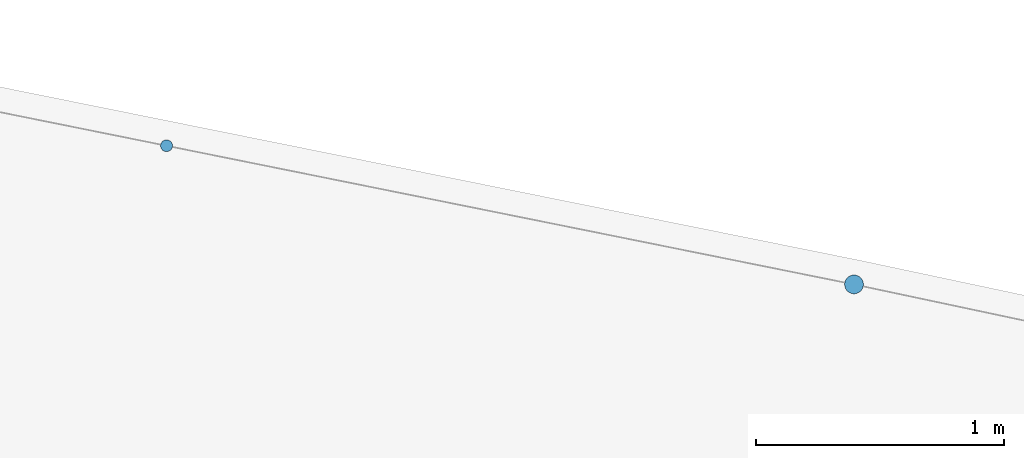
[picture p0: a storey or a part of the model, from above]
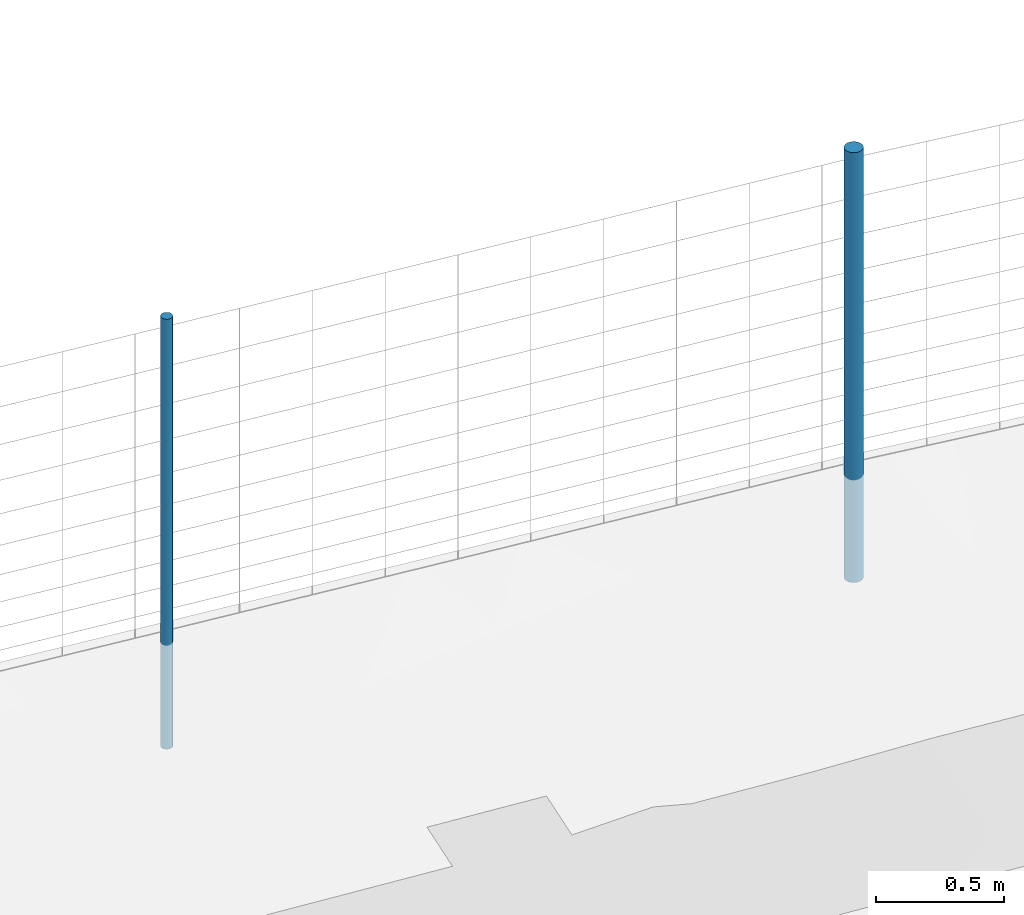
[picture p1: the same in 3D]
Properties of the parts of a building model (IFC4)

# File
Description: ViewDefinition [CoordinationView]
File name: Casa_Sobreposta_Implantada.ifc
Time: 2026-10-02T16:17:10
Written by: IfcOpenShell 0.8.0
Made in: IfcOpenShell 0.8.0

# IfcProject, Casa / Lares · R09 · Telhado tradicional
Pset_CasaModel - Design: R09 / telha / lower hybrid podium and ground-supported parking; ReferenceFile: 260617_CasaDFL_Estrutura_Terreno.ifc; ModelStatus: DESIGN_STUDY; North: Survey grid +Y; Ramp: No exterior pedestrian ramp or vehicular bridge; EngineeringStatus: Member sizes, foundations, connections, bracing and environmental performance not verified; GroundFFL_m: 14.65; AreaLimit_m2: 250; CountedGeometricArea_m2: 163.712; GreenhouseExcludedByUser: no; BalconiesExcludedByClient: yes; CoveredGroundBalcony_m2: 132.714; PlanningComplianceEstablished: no; AreaBasis: Client-confirmed 250 m2 allowance: parking, cistern, balconies and open greenhouse excluded; enclosed upper rooms and stair enclosures count. Any storage would count. Geometric study, no independent PDM verification.

# IfcSite, Lares · Rua das Mercês · artigo 4771
Pset_SurveySource - File: GN_09.26_213 Lares.dwg; SHA256: 0bca0a0751148bad1398f92d81b795428f94a57fea5e37dec0e125cea70402a1; Area_m2: 1636.5; BoundaryHandle: 31B; CoordinateReference: PT-TM06 / ETRS89; TerrainStatus: Proposed grading; original survey in separate IFC

# IfcBuilding, Casa Sobreposta
Pset_CasaPlacement - GroundFloorSurveyLevel_m: 14.65; UpperFloor: no; MoveEast_m: 3; MoveSouth_m: 0.5; RotationFromGridEast_deg: -8.5; BoundarySetbackRequired_m: 3; RuleBasis: User project constraint
Pset_CasaRevision09 - Variant: telha; HybridPodium: yes; ParkingGroundSupported: yes; GroundFFL_m: 14.65; TerraceFFL_m: 14.61; VehicularBridgeLength_m: 0; AccessGabions: no; Cut_m3: 96.4024; Fill_m3: 5.19635; EarthworkExclusions: Topsoil, foundation/service trenches, soil replacement, construction working space and bulking; CoveredGroundBalconyClassification: EXCLUDED_BY_CLIENT; WindCapacityVerified: no

# IfcBuildingStorey (2)
In: Casa Sobreposta
Name | Elevation (m)
00 · Habitação e estacionamento | 14.65
-01 · Cisterna sob o terraço | 12.05

# IfcSpace (11)
In: 00 · Habitação e estacionamento
Pset_CasaProvenance - DesignSource: Casa Sobreposta / configuration.json; ReferenceFile: 260617_CasaDFL_Estrutura_Terreno.ifc; ConstructionBasis: DESIGN_ASSUMPTION; Note: Functional zone from configurator; overlaps with partition footprints removed on ground floor. Not certified usable floor area.
Name | PredefinedType | NetFloorArea (m2)
Sala | INTERNAL | 31.359
Cozinha | INTERNAL | 9.94248
Banho | INTERNAL | 7.19804
WC | INTERNAL | 1.231
Serviço | INTERNAL | 4.16058
Acesso IS | INTERNAL | 3.99017
Quarto 1 | INTERNAL | 13.1145
Quarto 2 | INTERNAL | 13.1145
Quarto / escritório | INTERNAL | 37.8909
Circulação | INTERNAL | 18.1139
Estacionamento · 2 lugares | EXTERNAL | 32.55

# IfcAnnotation (4)
Pset_CasaProvenance - DesignSource: Casa Sobreposta / configuration.json; ReferenceFile: 260617_CasaDFL_Estrutura_Terreno.ifc; ConstructionBasis: DESIGN_ASSUMPTION
Name | In
Lugar P1 · 2.50 x 5.00 m | 00 · Habitação e estacionamento
Lugar P2 · 2.50 x 5.00 m | 00 · Habitação e estacionamento
Limite levantado · 31B | Lares · Rua das Mercês · artigo 4771
Afastamento de implantação · 3 m | Lares · Rua das Mercês · artigo 4771

# IfcBeam (11)
In: 00 · Habitação e estacionamento
Material: Betão armado / Stahlbeton
Pset_CasaProvenance - DesignSource: Casa Sobreposta / configuration.json; ReferenceFile: 260617_CasaDFL_Estrutura_Terreno.ifc; ConstructionBasis: DESIGN_ASSUMPTION
Name
8 x Pódio suspenso · viga transversal
3 x Pódio suspenso · viga longitudinal

# IfcBeam: TIMBER0.140x0.220 / timber (5)
In: 00 · Habitação e estacionamento
Type - Material: Madeira / Bauholz
Pset_CasaProvenance - DesignSource: Casa Sobreposta / configuration.json; ReferenceFile: 260617_CasaDFL_Estrutura_Terreno.ifc; ConstructionBasis: DESIGN_ASSUMPTION; Note: Visible timber concept; strength class, deflection, stability, wind and fire design pending.

# IfcBeam: TIMBER0.160x0.220 / timber (4)
In: 00 · Habitação e estacionamento
Type - Material: Madeira / Bauholz
Pset_CasaProvenance - DesignSource: Casa Sobreposta / configuration.json; ReferenceFile: 260617_CasaDFL_Estrutura_Terreno.ifc; ConstructionBasis: DESIGN_ASSUMPTION; Note: Visible timber concept; strength class, deflection, stability, wind and fire design pending.
Name
2 x Cobertura · frechal longitudinal
2 x Varanda coberta · frechal

# IfcBeam: TIMBER0.160x0.240 / timber (12)
In: 00 · Habitação e estacionamento
Type - Material: Madeira / Bauholz
Pset_CasaProvenance - DesignSource: Casa Sobreposta / configuration.json; ReferenceFile: 260617_CasaDFL_Estrutura_Terreno.ifc; ConstructionBasis: DESIGN_ASSUMPTION; Note: Visible timber concept; strength class, deflection, stability, wind and fire design pending.

# IfcBuildingElementProxy: Acesso · caixa de retenção de sedimentos (2)
In: Lares · Rua das Mercês · artigo 4771
PredefinedType: USERDEFINED; Material: Caleiras · betão
Pset_CasaProvenance - DesignSource: Casa Sobreposta / configuration.json; ReferenceFile: 260617_CasaDFL_Estrutura_Terreno.ifc; ConstructionBasis: DESIGN_ASSUMPTION

# IfcBuildingElementProxy: Acesso · dreno lateral raso · leito drenante (74)
In: Lares · Rua das Mercês · artigo 4771
PredefinedType: USERDEFINED; Material: Brita drenante
Pset_CasaProvenance - DesignSource: Casa Sobreposta / configuration.json; ReferenceFile: 260617_CasaDFL_Estrutura_Terreno.ifc; ConstructionBasis: DESIGN_ASSUMPTION; Note: R09 concept geometry; dimensions and connections not structurally verified.

# IfcBuildingElementProxy: Cisterna · água a 2,00 m, hipótese
In: -01 · Cisterna sob o terraço
PredefinedType: USERDEFINED; Material: Água pluvial · nível ilustrativo
Pset_CasaProvenance - DesignSource: Casa Sobreposta / configuration.json; ReferenceFile: 260617_CasaDFL_Estrutura_Terreno.ifc; ConstructionBasis: DESIGN_ASSUMPTION; Note: Illustrative water envelope, not concrete or a certified operating capacity.

# IfcBuildingElementProxy: Cobertura · caleira pluvial para cisterna (2)
In: 00 · Habitação e estacionamento
PredefinedType: USERDEFINED; Material: Aço galvanizado / Stahl verzinkt
Pset_CasaProvenance - DesignSource: Casa Sobreposta / configuration.json; ReferenceFile: 260617_CasaDFL_Estrutura_Terreno.ifc; ConstructionBasis: DESIGN_ASSUMPTION

# IfcBuildingElementProxy: Interceção · caleira estacionamento · leito drenante (8)
In: Lares · Rua das Mercês · artigo 4771
PredefinedType: USERDEFINED; Material: Brita drenante
Pset_CasaProvenance - DesignSource: Casa Sobreposta / configuration.json; ReferenceFile: 260617_CasaDFL_Estrutura_Terreno.ifc; ConstructionBasis: DESIGN_ASSUMPTION; Note: R09 concept geometry; dimensions and connections not structurally verified.

# IfcBuildingElementProxy: Interceção · caleira rua · leito drenante (8)
In: Lares · Rua das Mercês · artigo 4771
PredefinedType: USERDEFINED; Material: Brita drenante
Pset_CasaProvenance - DesignSource: Casa Sobreposta / configuration.json; ReferenceFile: 260617_CasaDFL_Estrutura_Terreno.ifc; ConstructionBasis: DESIGN_ASSUMPTION; Note: R09 concept geometry; dimensions and connections not structurally verified.

# IfcBuildingElementProxy: Trepadeiras · floreira (10)
In: 00 · Habitação e estacionamento
PredefinedType: USERDEFINED; Material: Betão armado / Stahlbeton
Pset_CasaProvenance - DesignSource: Casa Sobreposta / configuration.json; ReferenceFile: 260617_CasaDFL_Estrutura_Terreno.ifc; ConstructionBasis: DESIGN_ASSUMPTION; Note: Indicative planter; soil volume, irrigation, root space and waterproofing to design.

# IfcColumn (48)
In: 00 · Habitação e estacionamento
Material: Betão armado / Stahlbeton
Pset_CasaProvenance - DesignSource: Casa Sobreposta / configuration.json; ReferenceFile: 260617_CasaDFL_Estrutura_Terreno.ifc
Name | ConstructionBasis
18 x Casa térrea · pedestal | ADAPTED_REFERENCE
24 x Pódio suspenso · apoio sobre o terreno | DESIGN_ASSUMPTION
6 x Varanda coberta · pedestal enterrado | DESIGN_ASSUMPTION

# IfcColumn: IPE240 / steel (18)
In: 00 · Habitação e estacionamento
Type - Material: Aço pintado / Stahl lackiert
Pset_CasaProvenance - DesignSource: Casa Sobreposta / configuration.json; ReferenceFile: 260617_CasaDFL_Estrutura_Terreno.ifc; ConstructionBasis: ADAPTED_REFERENCE; Note: Reference section; spans, stability and connections require design.

# IfcColumn: RHS80x60x4 / steel (4)
In: 00 · Habitação e estacionamento
Type - Material: Aço pintado / Stahl lackiert
Pset_CasaProvenance - DesignSource: Casa Sobreposta / configuration.json; ReferenceFile: 260617_CasaDFL_Estrutura_Terreno.ifc; ConstructionBasis: DESIGN_ASSUMPTION; Note: Reference section; spans, stability and connections require design.

# IfcColumn: TIMBER0.160x0.160 / timber (24)
In: 00 · Habitação e estacionamento
Type - Material: Madeira / Bauholz
Pset_CasaProvenance - DesignSource: Casa Sobreposta / configuration.json; ReferenceFile: 260617_CasaDFL_Estrutura_Terreno.ifc; ConstructionBasis: DESIGN_ASSUMPTION; Note: Visible timber concept; strength class, deflection, stability, wind and fire design pending.

# IfcCovering (15)
Pset_CasaProvenance - DesignSource: Casa Sobreposta / configuration.json; ReferenceFile: 260617_CasaDFL_Estrutura_Terreno.ifc; ConstructionBasis: DESIGN_ASSUMPTION
Name | In | PredefinedType | Material
2 x Cobertura · forro de madeira | 00 · Habitação e estacionamento | CLADDING | Madeira / Bauholz
2 x Cobertura · isolamento | 00 · Habitação e estacionamento | INSULATION | Lã mineral / Mineralwolle 2
2 x Cobertura · membrana | 00 · Habitação e estacionamento | MEMBRANE | Membrana impermeável — hipótese
Cobertura · telhas individualizadas 1 | 00 · Habitação e estacionamento | ROOFING | Telha cerâmica · tile0 | Pset_CasaProvenance - Note: R09 concept geometry; dimensions and connections not structurally verified.
Cobertura · telhas individualizadas 2 | 00 · Habitação e estacionamento | ROOFING | Telha cerâmica · tile1 | Pset_CasaProvenance - Note: R09 concept geometry; dimensions and connections not structurally verified.
Cobertura · telhas individualizadas 3 | 00 · Habitação e estacionamento | ROOFING | Telha cerâmica · tile2 | Pset_CasaProvenance - Note: R09 concept geometry; dimensions and connections not structurally verified.
Cobertura · cumeeira cerâmica | 00 · Habitação e estacionamento | ROOFING | Telha cerâmica · tile1
Cisterna · camada drenante 100 mm | -01 · Cisterna sob o terraço | FLOORING | Brita drenante
Cisterna · impermeabilização poente | -01 · Cisterna sob o terraço | MEMBRANE | Membrana impermeável — hipótese
Cisterna · impermeabilização norte | -01 · Cisterna sob o terraço | MEMBRANE | Membrana impermeável — hipótese
Cisterna · impermeabilização sul | -01 · Cisterna sob o terraço | MEMBRANE | Membrana impermeável — hipótese
Cisterna · impermeabilização nascente | -01 · Cisterna sob o terraço | MEMBRANE | Membrana impermeável — hipótese

# IfcDoor (18)
In: 00 · Habitação e estacionamento
PredefinedType: DOOR
Pset_CasaProvenance - DesignSource: Casa Sobreposta / configuration.json; ReferenceFile: 260617_CasaDFL_Estrutura_Terreno.ifc
Name | OverallHeight (m) | OverallWidth (m) | OperationType | Material | ConstructionBasis
Porta interior 1 | 2.1 | 0.830093 | SINGLE_SWING_LEFT | OSB | ADAPTED_REFERENCE
Porta interior 2 | 2.1 | 0.830093 | SINGLE_SWING_LEFT | OSB | ADAPTED_REFERENCE
Porta interior 3 | 2.1 | 0.730086 | SINGLE_SWING_LEFT | OSB | ADAPTED_REFERENCE
Porta interior 4 | 2.1 | 0.830092 | SINGLE_SWING_LEFT | OSB | ADAPTED_REFERENCE
Porta interior 5 | 2.1 | 0.830077 | SINGLE_SWING_LEFT | OSB | ADAPTED_REFERENCE
Porta interior 6 | 2.1 | 0.730017 | SINGLE_SWING_LEFT | OSB | ADAPTED_REFERENCE
Porta do estacionamento | 2.1 | 0.83 | SINGLE_SWING_LEFT | Aço pintado / Stahl lackiert | ADAPTED_REFERENCE
Folha de correr sul 2 | 3 | 1.97133 | SLIDING_TO_LEFT | Vidro / Normalglas | DESIGN_ASSUMPTION
Folha de correr sul 4 | 3 | 1.97133 | SLIDING_TO_LEFT | Vidro / Normalglas | DESIGN_ASSUMPTION
Folha de correr sul 6 | 3 | 1.97133 | SLIDING_TO_LEFT | Vidro / Normalglas | DESIGN_ASSUMPTION
Folha de correr sul 8 | 3 | 1.97133 | SLIDING_TO_LEFT | Vidro / Normalglas | DESIGN_ASSUMPTION
Folha de correr sul 10 | 3 | 1.97133 | SLIDING_TO_LEFT | Vidro / Normalglas | DESIGN_ASSUMPTION
Folha de correr sul 12 | 3 | 0.614 | SLIDING_TO_LEFT | Vidro / Normalglas | DESIGN_ASSUMPTION
Fachada poente integralmente envidraçada · módulo 4 | 3 | 1.55 | SLIDING_TO_LEFT | Vidro / Normalglas | DESIGN_ASSUMPTION | Pset_CasaGlazedFacade - Revision: R02 · kiwi pergola; Facade: WEST / highlighted end in user sketch; Infill: Full-height glazing; no opaque infill; GlazingSpecification: 8 mm nominal representation only; insulated safety glazing assembly to specify
2 x Contentor · porta dupla | 2.39 | 1.17 | SINGLE_SWING_LEFT | Contentor · pintura 1 | DESIGN_ASSUMPTION
2 x Contentor · porta dupla | 2.39 | 1.17 | SINGLE_SWING_LEFT | Contentor · pintura 2 | DESIGN_ASSUMPTION

# IfcElementAssembly: CISTERN_PODIUM, Pódio · terraço, casa térrea e cisterna
In: 00 · Habitação e estacionamento
PredefinedType: USERDEFINED
Pset_CasaProvenance - DesignSource: Casa Sobreposta / configuration.json; ReferenceFile: 260617_CasaDFL_Estrutura_Terreno.ifc; ConstructionBasis: DESIGN_ASSUMPTION
Pset_CasaUndercroft - NaturalGroundRetained: no; EnclosedStorage: no; Use: Open ventilated sloping void; not a habitable or storage storey; StructuralStatus: Concept slab, beams, piers and foundation sizes; geotechnical and structural design pending
Pset_CasaPodium - TankGrossPlan_m2: 23; TankBaseLevel_m: 12.05; MinimumInternalHeight_m: 2.31; FloorSupport: Hybrid podium: west spans retained slope; local formation east; parking supported by soil; PlanningAssumption: Cistern excluded from 250 m2 by explicit user confirmation 2026-10-02

# IfcElementAssembly: COVERED_PODIUM_BALCONY, Varanda coberta · continuação integral da cobertura
In: 00 · Habitação e estacionamento
PredefinedType: USERDEFINED
Pset_CasaProvenance - DesignSource: Casa Sobreposta / configuration.json; ReferenceFile: 260617_CasaDFL_Estrutura_Terreno.ifc; ConstructionBasis: DESIGN_ASSUMPTION

# IfcElementAssembly: EXISTING_SHIPPING_CONTAINER (2)
In: 00 · Habitação e estacionamento
PredefinedType: USERDEFINED
Pset_CasaProvenance - DesignSource: Casa Sobreposta / configuration.json; ReferenceFile: 260617_CasaDFL_Estrutura_Terreno.ifc; ConstructionBasis: DESIGN_ASSUMPTION
Pset_CasaExistingContext - Length_m: 6; WidthAssumed_m: 2.44; HeightAssumed_m: 2.59; Location: Digitised visible roofs from signed orthophoto; fitted 6 x 2.44 m, provisional +/- 0.50 m, verify ground corners; Status: Existing context; not included in new building setback or new floor-area schedule; Colour: Illustrative, condition not surveyed
Name
Contentor existente 1 · 6 m
Contentor existente 2 · 6 m

# IfcElementAssembly: LIVING_SHADE_TRELLIS, Fachada sul e pátio · estrutura e trepadeiras
In: 00 · Habitação e estacionamento
PredefinedType: USERDEFINED
Pset_CasaProvenance - DesignSource: Casa Sobreposta / configuration.json; ReferenceFile: 260617_CasaDFL_Estrutura_Terreno.ifc; ConstructionBasis: DESIGN_ASSUMPTION

# IfcFooting (64)
Material: Betão armado / Stahlbeton
Pset_CasaProvenance - DesignSource: Casa Sobreposta / configuration.json; ReferenceFile: 260617_CasaDFL_Estrutura_Terreno.ifc
Name | In | PredefinedType | ConstructionBasis
18 x Casa térrea · sapata | 00 · Habitação e estacionamento | PAD_FOOTING | ADAPTED_REFERENCE
Cisterna · sapata corrida poente | -01 · Cisterna sob o terraço | STRIP_FOOTING | DESIGN_ASSUMPTION
Cisterna · sapata corrida norte | -01 · Cisterna sob o terraço | STRIP_FOOTING | DESIGN_ASSUMPTION
Cisterna · sapata corrida sul | -01 · Cisterna sob o terraço | STRIP_FOOTING | DESIGN_ASSUMPTION
Cisterna · sapata corrida nascente | -01 · Cisterna sob o terraço | STRIP_FOOTING | DESIGN_ASSUMPTION
4 x Jardim · apoio | 00 · Habitação e estacionamento | PAD_FOOTING | DESIGN_ASSUMPTION
24 x Pódio suspenso · sapata pontual | 00 · Habitação e estacionamento | PAD_FOOTING | DESIGN_ASSUMPTION
6 x Varanda coberta · sapata no estacionamento | 00 · Habitação e estacionamento | PAD_FOOTING | DESIGN_ASSUMPTION
8 x Contentor · bloco de apoio nivelado | 00 · Habitação e estacionamento | PAD_FOOTING | DESIGN_ASSUMPTION

# IfcFurnishingElement, Ilha da cozinha · esquema
In: 00 · Habitação e estacionamento
Material: OSB
Pset_CasaProvenance - DesignSource: Casa Sobreposta / configuration.json; ReferenceFile: 260617_CasaDFL_Estrutura_Terreno.ifc; ConstructionBasis: ADAPTED_REFERENCE

# IfcGeographicElement, Terreno · R09 com telha, cisterna e drenagem
In: Lares · Rua das Mercês · artigo 4771
PredefinedType: TERRAIN; Material: Terreno · modelação proposta
Pset_CasaProvenance - DesignSource: Casa Sobreposta / configuration.json; ReferenceFile: 260617_CasaDFL_Estrutura_Terreno.ifc; ConstructionBasis: DESIGN_ASSUMPTION

# IfcGeographicElement: ANALYTICAL_CUT_VOLUME, Escavação · diferença entre terrenos
In: Lares · Rua das Mercês · artigo 4771
PredefinedType: USERDEFINED; Material: Escavação · volume analítico
Pset_CasaProvenance - DesignSource: Casa Sobreposta / configuration.json; ReferenceFile: 260617_CasaDFL_Estrutura_Terreno.ifc; ConstructionBasis: DESIGN_ASSUMPTION; Note: ANALYTICAL VOLUME, not additional constructed material. Closed wedges between surveyed and proposed TIN, split where sign changes. Excludes stripping, foundations, services and bulking.
Pset_CasaEarthworks - Kind: CUT; Volume_m3: 96.4024; Method: Exact signed integration of linear proposed/existing display TIN, splitting zero crossings; Excluded: Topsoil stripping, foundation/service trenches, soil replacement, bulking and shrinkage; Status: CONCEPT_GEOMETRIC_VOLUME; not a measured bill of works; DefaultVisibility: Hide analytical volumes in normal model views
Qto_CasaEarthworks - NetVolume: 96.4024 m3

# IfcGeographicElement: ANALYTICAL_FILL_VOLUME, Aterro · diferença entre terrenos
In: Lares · Rua das Mercês · artigo 4771
PredefinedType: USERDEFINED; Material: Aterro · volume analítico
Pset_CasaProvenance - DesignSource: Casa Sobreposta / configuration.json; ReferenceFile: 260617_CasaDFL_Estrutura_Terreno.ifc; ConstructionBasis: DESIGN_ASSUMPTION; Note: ANALYTICAL VOLUME, not additional constructed material. Closed wedges between surveyed and proposed TIN, split where sign changes. Excludes stripping, foundations, services and bulking.
Pset_CasaEarthworks - Kind: FILL; Volume_m3: 5.19635; Method: Exact signed integration of linear proposed/existing display TIN, splitting zero crossings; Excluded: Topsoil stripping, foundation/service trenches, soil replacement, bulking and shrinkage; Status: CONCEPT_GEOMETRIC_VOLUME; not a measured bill of works; DefaultVisibility: Hide analytical volumes in normal model views
Qto_CasaEarthworks - NetVolume: 5.19635 m3

# IfcGeographicElement: Acesso trapezoidal · 8,60 m no pódio / 5,00 m na rua
In: Lares · Rua das Mercês · artigo 4771
PredefinedType: USERDEFINED; Material: Pavimento rugoso · betão vassourado
Pset_CasaProvenance - DesignSource: Casa Sobreposta / configuration.json; ReferenceFile: 260617_CasaDFL_Estrutura_Terreno.ifc; ConstructionBasis: DESIGN_ASSUMPTION

# IfcGeographicElement: Marcação no solo · árvore indicativa 01
In: Lares · Rua das Mercês · artigo 4771
PredefinedType: USERDEFINED; Material: Marcação de plantação · linha no terreno
Pset_CasaProvenance - DesignSource: Casa Sobreposta / configuration.json; ReferenceFile: 260617_CasaDFL_Estrutura_Terreno.ifc; ConstructionBasis: DESIGN_ASSUMPTION; Note: R09 concept geometry; dimensions and connections not structurally verified.
Pset_PlantingReserve - Diameter_m: 3; Representation: GROUND_CIRCLE_ONLY; Species: UNSPECIFIED; Status: Indicative position and spacing, not a mature canopy guarantee

# IfcGeographicElement: Marcação no solo · árvore indicativa 02
In: Lares · Rua das Mercês · artigo 4771
PredefinedType: USERDEFINED; Material: Marcação de plantação · linha no terreno
Pset_CasaProvenance - DesignSource: Casa Sobreposta / configuration.json; ReferenceFile: 260617_CasaDFL_Estrutura_Terreno.ifc; ConstructionBasis: DESIGN_ASSUMPTION; Note: R09 concept geometry; dimensions and connections not structurally verified.
Pset_PlantingReserve - Diameter_m: 3; Representation: GROUND_CIRCLE_ONLY; Species: UNSPECIFIED; Status: Indicative position and spacing, not a mature canopy guarantee

# IfcGeographicElement: Marcação no solo · árvore indicativa 03
In: Lares · Rua das Mercês · artigo 4771
PredefinedType: USERDEFINED; Material: Marcação de plantação · linha no terreno
Pset_CasaProvenance - DesignSource: Casa Sobreposta / configuration.json; ReferenceFile: 260617_CasaDFL_Estrutura_Terreno.ifc; ConstructionBasis: DESIGN_ASSUMPTION; Note: R09 concept geometry; dimensions and connections not structurally verified.
Pset_PlantingReserve - Diameter_m: 3; Representation: GROUND_CIRCLE_ONLY; Species: UNSPECIFIED; Status: Indicative position and spacing, not a mature canopy guarantee

# IfcGeographicElement: Marcação no solo · árvore indicativa 04
In: Lares · Rua das Mercês · artigo 4771
PredefinedType: USERDEFINED; Material: Marcação de plantação · linha no terreno
Pset_CasaProvenance - DesignSource: Casa Sobreposta / configuration.json; ReferenceFile: 260617_CasaDFL_Estrutura_Terreno.ifc; ConstructionBasis: DESIGN_ASSUMPTION; Note: R09 concept geometry; dimensions and connections not structurally verified.
Pset_PlantingReserve - Diameter_m: 3; Representation: GROUND_CIRCLE_ONLY; Species: UNSPECIFIED; Status: Indicative position and spacing, not a mature canopy guarantee

# IfcGeographicElement: Marcação no solo · árvore indicativa 05
In: Lares · Rua das Mercês · artigo 4771
PredefinedType: USERDEFINED; Material: Marcação de plantação · linha no terreno
Pset_CasaProvenance - DesignSource: Casa Sobreposta / configuration.json; ReferenceFile: 260617_CasaDFL_Estrutura_Terreno.ifc; ConstructionBasis: DESIGN_ASSUMPTION; Note: R09 concept geometry; dimensions and connections not structurally verified.
Pset_PlantingReserve - Diameter_m: 3; Representation: GROUND_CIRCLE_ONLY; Species: UNSPECIFIED; Status: Indicative position and spacing, not a mature canopy guarantee

# IfcGeographicElement: Marcação no solo · árvore indicativa 06
In: Lares · Rua das Mercês · artigo 4771
PredefinedType: USERDEFINED; Material: Marcação de plantação · linha no terreno
Pset_CasaProvenance - DesignSource: Casa Sobreposta / configuration.json; ReferenceFile: 260617_CasaDFL_Estrutura_Terreno.ifc; ConstructionBasis: DESIGN_ASSUMPTION; Note: R09 concept geometry; dimensions and connections not structurally verified.
Pset_PlantingReserve - Diameter_m: 3; Representation: GROUND_CIRCLE_ONLY; Species: UNSPECIFIED; Status: Indicative position and spacing, not a mature canopy guarantee

# IfcGeographicElement: Marcação no solo · árvore indicativa 07
In: Lares · Rua das Mercês · artigo 4771
PredefinedType: USERDEFINED; Material: Marcação de plantação · linha no terreno
Pset_CasaProvenance - DesignSource: Casa Sobreposta / configuration.json; ReferenceFile: 260617_CasaDFL_Estrutura_Terreno.ifc; ConstructionBasis: DESIGN_ASSUMPTION; Note: R09 concept geometry; dimensions and connections not structurally verified.
Pset_PlantingReserve - Diameter_m: 3; Representation: GROUND_CIRCLE_ONLY; Species: UNSPECIFIED; Status: Indicative position and spacing, not a mature canopy guarantee

# IfcGeographicElement: Marcação no solo · árvore indicativa 08
In: Lares · Rua das Mercês · artigo 4771
PredefinedType: USERDEFINED; Material: Marcação de plantação · linha no terreno
Pset_CasaProvenance - DesignSource: Casa Sobreposta / configuration.json; ReferenceFile: 260617_CasaDFL_Estrutura_Terreno.ifc; ConstructionBasis: DESIGN_ASSUMPTION; Note: R09 concept geometry; dimensions and connections not structurally verified.
Pset_PlantingReserve - Diameter_m: 3; Representation: GROUND_CIRCLE_ONLY; Species: UNSPECIFIED; Status: Indicative position and spacing, not a mature canopy guarantee

# IfcGeographicElement: Marcação no solo · árvore indicativa 09
In: Lares · Rua das Mercês · artigo 4771
PredefinedType: USERDEFINED; Material: Marcação de plantação · linha no terreno
Pset_CasaProvenance - DesignSource: Casa Sobreposta / configuration.json; ReferenceFile: 260617_CasaDFL_Estrutura_Terreno.ifc; ConstructionBasis: DESIGN_ASSUMPTION; Note: R09 concept geometry; dimensions and connections not structurally verified.
Pset_PlantingReserve - Diameter_m: 3; Representation: GROUND_CIRCLE_ONLY; Species: UNSPECIFIED; Status: Indicative position and spacing, not a mature canopy guarantee

# IfcGeographicElement: Marcação no solo · árvore indicativa 10
In: Lares · Rua das Mercês · artigo 4771
PredefinedType: USERDEFINED; Material: Marcação de plantação · linha no terreno
Pset_CasaProvenance - DesignSource: Casa Sobreposta / configuration.json; ReferenceFile: 260617_CasaDFL_Estrutura_Terreno.ifc; ConstructionBasis: DESIGN_ASSUMPTION; Note: R09 concept geometry; dimensions and connections not structurally verified.
Pset_PlantingReserve - Diameter_m: 3; Representation: GROUND_CIRCLE_ONLY; Species: UNSPECIFIED; Status: Indicative position and spacing, not a mature canopy guarantee

# IfcGeographicElement: VEGETATION, Trepadeiras · folhas individuais, estado ilustrativo
In: 00 · Habitação e estacionamento
PredefinedType: USERDEFINED; Material: Folhagem · trepadeiras
Pset_CasaProvenance - DesignSource: Casa Sobreposta / configuration.json; ReferenceFile: 260617_CasaDFL_Estrutura_Terreno.ifc; ConstructionBasis: DESIGN_ASSUMPTION; Note: Procedural leaves for visual intent only; no predicted growth, species performance or wind protection.

# IfcMember (154)
In: 00 · Habitação e estacionamento
Pset_CasaProvenance - DesignSource: Casa Sobreposta / configuration.json; ReferenceFile: 260617_CasaDFL_Estrutura_Terreno.ifc; ConstructionBasis: DESIGN_ASSUMPTION
Name | Material
4 x Contentor · canto | Contentor · pintura 1
50 x Contentor · nervura lateral | Contentor · pintura 1
23 x Contentor · nervura cobertura | Contentor · pintura 1
4 x Contentor · canto | Contentor · pintura 2
50 x Contentor · nervura lateral | Contentor · pintura 2
23 x Contentor · nervura cobertura | Contentor · pintura 2

# IfcMember: C240 / steel (2)
In: 00 · Habitação e estacionamento
Type - Material: Aço pintado / Stahl lackiert
Pset_CasaProvenance - DesignSource: Casa Sobreposta / configuration.json; ReferenceFile: 260617_CasaDFL_Estrutura_Terreno.ifc; ConstructionBasis: ADAPTED_REFERENCE; Note: Reference section; spans, stability and connections require design.

# IfcMember: D0.004 / galvanized (117)
In: 00 · Habitação e estacionamento
Type - Material: Aço galvanizado / Stahl verzinkt
Pset_CasaProvenance - DesignSource: Casa Sobreposta / configuration.json; ReferenceFile: 260617_CasaDFL_Estrutura_Terreno.ifc; ConstructionBasis: DESIGN_ASSUMPTION; Note: Reference section; spans, stability and connections require design.
Name
50 x Trepadeiras · fio horizontal
67 x Trepadeiras · fio vertical

# IfcMember: D0.015 / vine_wood (627)
In: 00 · Habitação e estacionamento
Type - Material: Ramos de trepadeiras
Pset_CasaProvenance - DesignSource: Casa Sobreposta / configuration.json; ReferenceFile: 260617_CasaDFL_Estrutura_Terreno.ifc; ConstructionBasis: DESIGN_ASSUMPTION; Note: Reference section; spans, stability and connections require design.

# IfcMember: D0.025 / galvanized (8)
In: 00 · Habitação e estacionamento
Type - Material: Aço galvanizado / Stahl verzinkt
Pset_CasaProvenance - DesignSource: Casa Sobreposta / configuration.json; ReferenceFile: 260617_CasaDFL_Estrutura_Terreno.ifc; ConstructionBasis: DESIGN_ASSUMPTION; Note: Reference section; spans, stability and connections require design.

# IfcMember: D0.048 / galvanized (57)
In: Lares · Rua das Mercês · artigo 4771
Type - Material: Aço galvanizado / Stahl verzinkt
PredefinedType: POST
Pset_CasaProvenance - DesignSource: Casa Sobreposta / configuration.json; ReferenceFile: 260617_CasaDFL_Estrutura_Terreno.ifc; ConstructionBasis: DESIGN_ASSUMPTION; Note: Galvanised steel tube post, nominal; embedment, concrete base and strainer bracing to detail.

# IfcMember: D0.076 / galvanized (26)
In: Lares · Rua das Mercês · artigo 4771
Type - Material: Aço galvanizado / Stahl verzinkt
PredefinedType: POST
Pset_CasaProvenance - DesignSource: Casa Sobreposta / configuration.json; ReferenceFile: 260617_CasaDFL_Estrutura_Terreno.ifc; ConstructionBasis: DESIGN_ASSUMPTION; Note: Galvanised steel tube post, nominal; embedment, concrete base and strainer bracing to detail.

# IfcMember: R0.018 / galvanized (557)
In: Lares · Rua das Mercês · artigo 4771
Type - Material: Aço galvanizado / Stahl verzinkt
Pset_CasaProvenance - DesignSource: Casa Sobreposta / configuration.json; ReferenceFile: 260617_CasaDFL_Estrutura_Terreno.ifc; ConstructionBasis: DESIGN_ASSUMPTION; Note: Reference section; spans, stability and connections require design.
Name
469 x Acesso · dreno lateral raso · grelha
32 x Interceção · caleira rua · grelha
56 x Interceção · caleira estacionamento · grelha

# IfcMember: R0.025 / galvanized (8)
In: 00 · Habitação e estacionamento
Type - Material: Aço galvanizado / Stahl verzinkt
Pset_CasaProvenance - DesignSource: Casa Sobreposta / configuration.json; ReferenceFile: 260617_CasaDFL_Estrutura_Terreno.ifc; ConstructionBasis: DESIGN_ASSUMPTION; Note: Reference section; spans, stability and connections require design.

# IfcMember: R0.035 / steel (68)
In: 00 · Habitação e estacionamento
Type - Material: Aço pintado / Stahl lackiert
Pset_CasaProvenance - DesignSource: Casa Sobreposta / configuration.json; ReferenceFile: 260617_CasaDFL_Estrutura_Terreno.ifc; ConstructionBasis: ADAPTED_REFERENCE; Note: Reference section; spans, stability and connections require design.
Name
2 x Rasgo norte 1 · montante
2 x Rasgo norte 1 · travessa
2 x Rasgo norte 2 · montante
2 x Rasgo norte 2 · travessa
2 x Rasgo norte 3 · montante
2 x Rasgo norte 3 · travessa
2 x Rasgo norte 4 · montante
2 x Rasgo norte 4 · travessa
2 x Rasgo norte 5 · montante
2 x Rasgo norte 5 · travessa
2 x Rasgo norte 6 · montante
2 x Rasgo norte 6 · travessa
2 x Rasgo norte 7 · montante
2 x Rasgo norte 7 · travessa
2 x Folha de correr sul 2 · montante
2 x Folha de correr sul 2 · travessa
2 x Folha de correr sul 4 · montante
2 x Folha de correr sul 4 · travessa
2 x Folha de correr sul 6 · montante
2 x Folha de correr sul 6 · travessa
2 x Folha de correr sul 8 · montante
2 x Folha de correr sul 8 · travessa
2 x Folha de correr sul 10 · montante
2 x Folha de correr sul 10 · travessa
2 x Folha de correr sul 12 · montante
2 x Folha de correr sul 12 · travessa
2 x Fachada poente integralmente envidraçada · módulo 1 · montante
2 x Fachada poente integralmente envidraçada · módulo 1 · travessa
2 x Fachada poente integralmente envidraçada · módulo 2 · montante
2 x Fachada poente integralmente envidraçada · módulo 2 · travessa
2 x Fachada poente integralmente envidraçada · módulo 3 · montante
2 x Fachada poente integralmente envidraçada · módulo 3 · travessa
2 x Fachada poente integralmente envidraçada · módulo 4 · montante
2 x Fachada poente integralmente envidraçada · módulo 4 · travessa

# IfcMember: TIMBER0.045x0.060 / timber (30)
In: 00 · Habitação e estacionamento
Type - Material: Madeira / Bauholz
Pset_CasaProvenance - DesignSource: Casa Sobreposta / configuration.json; ReferenceFile: 260617_CasaDFL_Estrutura_Terreno.ifc; ConstructionBasis: DESIGN_ASSUMPTION; Note: Visible timber concept; strength class, deflection, stability, wind and fire design pending.

# IfcMember: TIMBER0.080x0.240 / timber (134)
In: 00 · Habitação e estacionamento
Type - Material: Madeira / Bauholz
Pset_CasaProvenance - DesignSource: Casa Sobreposta / configuration.json; ReferenceFile: 260617_CasaDFL_Estrutura_Terreno.ifc; ConstructionBasis: DESIGN_ASSUMPTION; Note: Visible timber concept; strength class, deflection, stability, wind and fire design pending.

# IfcMember: TIMBER0.100x0.160 / timber (24)
In: 00 · Habitação e estacionamento
Type - Material: Madeira / Bauholz
Pset_CasaProvenance - DesignSource: Casa Sobreposta / configuration.json; ReferenceFile: 260617_CasaDFL_Estrutura_Terreno.ifc; ConstructionBasis: DESIGN_ASSUMPTION; Note: Visible timber concept; strength class, deflection, stability, wind and fire design pending.

# IfcMember: TIMBER0.140x0.140 / timber (12)
In: 00 · Habitação e estacionamento
Type - Material: Madeira / Bauholz
Pset_CasaProvenance - DesignSource: Casa Sobreposta / configuration.json; ReferenceFile: 260617_CasaDFL_Estrutura_Terreno.ifc; ConstructionBasis: DESIGN_ASSUMPTION; Note: Visible timber concept; strength class, deflection, stability, wind and fire design pending.

# IfcMember: TIMBER0.160x0.240 / timber (24)
In: 00 · Habitação e estacionamento
Type - Material: Madeira / Bauholz
Pset_CasaProvenance - DesignSource: Casa Sobreposta / configuration.json; ReferenceFile: 260617_CasaDFL_Estrutura_Terreno.ifc; ConstructionBasis: DESIGN_ASSUMPTION; Note: Visible timber concept; strength class, deflection, stability, wind and fire design pending.

# IfcOpeningElement (20)
In: 00 · Habitação e estacionamento
PredefinedType: OPENING
Pset_CasaProvenance - DesignSource: Casa Sobreposta / configuration.json; ReferenceFile: 260617_CasaDFL_Estrutura_Terreno.ifc; ConstructionBasis: DESIGN_ASSUMPTION; Note: Real subtractive void
Name
Vão porta interior 1.1
Vão porta interior 1.2
Vão porta interior 2.1
Vão porta interior 2.2
Vão porta interior 3.1
Vão porta interior 3.2
Vão porta interior 4.1
Vão porta interior 4.2
Vão porta interior 5.1
Vão porta interior 6.1
Vão porta interior 6.2
Vão rasgo norte 1
Vão rasgo norte 2
Vão rasgo norte 3
Vão rasgo norte 4
Vão rasgo norte 5
Vão rasgo norte 6
Vão rasgo norte 7
Vão de acesso do estacionamento
Cisterna · abertura de inspeção

# IfcPipeSegment: D0.10 / galvanized (6)
In: 00 · Habitação e estacionamento
Type - Material: Aço galvanizado / Stahl verzinkt
Pset_CasaProvenance - DesignSource: Casa Sobreposta / configuration.json; ReferenceFile: 260617_CasaDFL_Estrutura_Terreno.ifc; ConstructionBasis: DESIGN_ASSUMPTION; Note: Nominal route to rainwater tank; Nominal gutter fall 0.2% to west; filter, first flush, sizing and overflow to detail. Separate from vehicle drainage.

# IfcPipeSegment: D0.16 / drain (4)
In: Lares · Rua das Mercês · artigo 4771
Type - Material: Caleiras · betão
Pset_CasaProvenance - DesignSource: Casa Sobreposta / configuration.json; ReferenceFile: 260617_CasaDFL_Estrutura_Terreno.ifc; ConstructionBasis: DESIGN_ASSUMPTION
Name | Note
Acesso · queda pluvial até coletor | Reference section; spans, stability and connections require design.
3 x Acesso · coletor separado da cisterna | Nominal DN160 spatial route only, not hydraulically sized. Silt/contaminant treatment and outlet/infiltration to design.

# IfcPlate (50)
In: 00 · Habitação e estacionamento
Pset_CasaProvenance - DesignSource: Casa Sobreposta / configuration.json; ReferenceFile: 260617_CasaDFL_Estrutura_Terreno.ifc; ConstructionBasis: DESIGN_ASSUMPTION
Name | PredefinedType | Material
18 x Cobertura · ligação madeira aço | SHEET | Aço galvanizado / Stahl verzinkt
Empena poente envidraçada | SHEET | Vidro / Normalglas
Cisterna · tampa estanque de inspeção | SHEET | Aço galvanizado / Stahl verzinkt | Pset_CasaProvenance - Note: Flush, closed 900 mm maintenance hatch; cover capacity and safe maintenance access to detail. Not a routine entrance.
24 x Varanda coberta · base metálica | SHEET | Aço galvanizado / Stahl verzinkt
2 x Contentor · chapa lateral |  | Contentor · pintura 1
Contentor · chapa de fundo |  | Contentor · pintura 1
2 x Contentor · chapa lateral |  | Contentor · pintura 2
Contentor · chapa de fundo |  | Contentor · pintura 2

# IfcRailing (8)
In: 00 · Habitação e estacionamento
PredefinedType: GUARDRAIL; Material: Aço pintado / Stahl lackiert
Pset_CasaProvenance - DesignSource: Casa Sobreposta / configuration.json; ReferenceFile: 260617_CasaDFL_Estrutura_Terreno.ifc; ConstructionBasis: DESIGN_ASSUMPTION; Note: Study guard 1.10 m; twin handrails at 0.70 and 0.90 m on ramp; loads and fixings unverified.
Name
Pódio · guarda sul
Pódio · guarda poente sul
Pódio · guarda poente norte
Pódio · guarda norte
2 x Jardim · corrimão poente
2 x Jardim · guarda do patamar

# IfcRailing: SHEEP_WIRE_FENCE (82)
In: Lares · Rua das Mercês · artigo 4771
PredefinedType: USERDEFINED; Material: Aço galvanizado / Stahl verzinkt
Pset_CasaProvenance - DesignSource: Casa Sobreposta / configuration.json; ReferenceFile: 260617_CasaDFL_Estrutura_Terreno.ifc; ConstructionBasis: DESIGN_ASSUMPTION; Note: R09 concept geometry; dimensions and connections not structurally verified.
Pset_CasaFence - Height_m: 1.5; Mesh: Galvanised sheep netting, graduated line wires, 0.30 m vertical stays; Status: CONCEPT; wire gauge, tensioning and posts to specify
Name | PostSpacing_m
Vedação · rede ovelheira 1.001 | 2.31221
Vedação · rede ovelheira 1.002 | 2.31221
Vedação · rede ovelheira 1.003 | 2.31221
Vedação · rede ovelheira 1.004 | 2.85062
Vedação · rede ovelheira 1.005 | 2.85062
Vedação · rede ovelheira 1.006 | 2.85062
Vedação · rede ovelheira 1.007 | 2.85062
Vedação · rede ovelheira 1.008 | 2.41772
Vedação · rede ovelheira 1.009 | 2.41772
Vedação · rede ovelheira 1.010 | 2.41772
Vedação · rede ovelheira 1.011 | 2.41772
Vedação · rede ovelheira 1.012 | 2.41772
Vedação · rede ovelheira 1.013 | 2.4459
Vedação · rede ovelheira 1.014 | 2.4459
Vedação · rede ovelheira 1.015 | 2.4459
Vedação · rede ovelheira 1.016 | 2.4459
Vedação · rede ovelheira 1.017 | 2.4459
Vedação · rede ovelheira 1.018 | 2.41457
Vedação · rede ovelheira 1.019 | 2.41457
Vedação · rede ovelheira 1.020 | 2.41457
Vedação · rede ovelheira 1.021 | 2.41457
Vedação · rede ovelheira 1.022 | 2.41457
Vedação · rede ovelheira 1.023 | 2.93474
Vedação · rede ovelheira 1.024 | 2.93474
Vedação · rede ovelheira 1.025 | 2.93474
Vedação · rede ovelheira 1.026 | 2.93474
Vedação · rede ovelheira 1.027 | 2.4949
Vedação · rede ovelheira 1.028 | 2.4949
Vedação · rede ovelheira 1.029 | 2.4949
Vedação · rede ovelheira 1.030 | 2.4949
Vedação · rede ovelheira 1.031 | 2.4949
Vedação · rede ovelheira 1.032 | 2.41477
Vedação · rede ovelheira 1.033 | 2.41477
Vedação · rede ovelheira 1.034 | 2.41477
Vedação · rede ovelheira 1.035 | 2.41477
Vedação · rede ovelheira 1.036 | 2.90303
Vedação · rede ovelheira 1.037 | 2.90303
Vedação · rede ovelheira 1.038 | 2.59069
Vedação · rede ovelheira 1.039 | 2.59069
Vedação · rede ovelheira 1.040 | 2.59069
Vedação · rede ovelheira 1.041 | 2.12292
Vedação · rede ovelheira 1.042 | 2.12292
Vedação · rede ovelheira 1.043 | 2.49871
Vedação · rede ovelheira 1.044 | 2.49871
Vedação · rede ovelheira 1.045 | 2.49871
Vedação · rede ovelheira 1.046 | 2.44661
Vedação · rede ovelheira 1.047 | 2.44661
Vedação · rede ovelheira 1.048 | 2.44661
Vedação · rede ovelheira 1.049 | 2.06726
Vedação · rede ovelheira 1.050 | 2.06726
Vedação · rede ovelheira 1.051 | 2.68804
Vedação · rede ovelheira 1.052 | 2.68804
Vedação · rede ovelheira 1.053 | 2.76823
Vedação · rede ovelheira 1.054 | 2.76823
Vedação · rede ovelheira 1.055 | 2.76823
Vedação · rede ovelheira 1.056 | 2.73364
Vedação · rede ovelheira 1.057 | 2.73364
Vedação · rede ovelheira 1.058 | 2.73364
Vedação · rede ovelheira 1.059 | 2.9388
Vedação · rede ovelheira 1.060 | 2.9388
Vedação · rede ovelheira 1.061 | 2.99875
Vedação · rede ovelheira 1.062 | 2.99875
Vedação · rede ovelheira 1.063 | 2.99875
Vedação · rede ovelheira 1.064 | 2.42137
Vedação · rede ovelheira 1.065 | 2.42137
Vedação · rede ovelheira 1.066 | 2.42137
Vedação · rede ovelheira 1.067 | 2.42137
Vedação · rede ovelheira 1.068 | 2.65677
Vedação · rede ovelheira 1.069 | 2.65677
Vedação · rede ovelheira 1.070 | 2.65677
Vedação · rede ovelheira 1.071 | 2.65677
Vedação · rede ovelheira 1.072 | 2.96086
Vedação · rede ovelheira 1.073 | 2.96086
Vedação · rede ovelheira 1.074 | 2.96086
Vedação · rede ovelheira 1.075 | 2.83036
Vedação · rede ovelheira 1.076 | 2.83036
Vedação · rede ovelheira 1.077 | 2.83036
Vedação · rede ovelheira 1.078 | 2.61662
Vedação · rede ovelheira 1.079 | 2.61662
Vedação · rede ovelheira 1.080 | 2.61662
Vedação · rede ovelheira 1.081 | 2.61662
Vedação · rede ovelheira 1.082 | 1.96455

# IfcRoof, Cobertura de telha · duas águas 30 graus
In: 00 · Habitação e estacionamento
PredefinedType: GABLE_ROOF; Material: Madeira / Bauholz
Pset_CasaProvenance - DesignSource: Casa Sobreposta / configuration.json; ReferenceFile: 260617_CasaDFL_Estrutura_Terreno.ifc; ConstructionBasis: DESIGN_ASSUMPTION
Pset_CasaRoof - Pitch_deg: 30; StoreysAboveGround: 1; AtticFloor: no; Interior: Open to sloping timber deck; no ceiling or upper floor; StructuralStatus: Concept only; 200 km/h verification from R05 greenhouse does not apply; CoversWholePodium: yes; RoofPlanLength_m: 38.8; RoofPlanWidth_m: 8.9; ThermalBuildUp: 20 mm timber deck + 160 mm insulation + membrane + ventilated battens + clay tile; assumptions

# IfcSanitaryTerminal (5)
In: 00 · Habitação e estacionamento
Material: Cerâmica sanitária — esquema
Pset_CasaProvenance - DesignSource: Casa Sobreposta / configuration.json; ReferenceFile: 260617_CasaDFL_Estrutura_Terreno.ifc; ConstructionBasis: DESIGN_ASSUMPTION; Note: Schematic fixture, not a manufacturer object.
Name | PredefinedType
Banheira | BATH
Lavatório 1 | WASHHANDBASIN
Lavatório 2 | WASHHANDBASIN
Sanita | TOILETPAN
Bancada de cozinha | TOILETPAN

# IfcSlab (9)
Pset_CasaProvenance - DesignSource: Casa Sobreposta / configuration.json; ReferenceFile: 260617_CasaDFL_Estrutura_Terreno.ifc; ConstructionBasis: DESIGN_ASSUMPTION
Name | In | PredefinedType | Material
Cisterna · laje de fundo 200 mm | -01 · Cisterna sob o terraço | BASESLAB | Betão armado / Stahlbeton
Pódio · laje da casa 250 mm | 00 · Habitação e estacionamento | FLOOR | Betão armado / Stahlbeton | Pset_CasaProvenance - Note: Suspended slab on discrete piers and grade beams. Natural slope retained where clear; local shallow excavation where beams meet rising ground. Sizes unverified.
Pódio · terraço e faixa de proteção sul | 00 · Habitação e estacionamento | FLOOR | Betão armado / Stahlbeton | Pset_CasaProvenance - Note: Terrace 40 mm below house. West terrace over void/cistern; shallow local formation to east. Parking is a separate ground-supported pavement.
Estacionamento · pavimento apoiado no solo | 00 · Habitação e estacionamento | BASESLAB | Betão armado / Stahlbeton | Pset_CasaProvenance - Note: R09 concept geometry; dimensions and connections not structurally verified.; Pset_CasaParking - GroundSupported: yes; LongitudinalGrade_percent: 2.5; Crossfall_percent: 4; HouseThresholdStep_m: 0.02; Status: Concept grading; pavement build-up and accessibility to detail
Jardim · patamar poente | 00 · Habitação e estacionamento | LANDING | Betão armado / Stahlbeton
2 x Contentor · piso ou teto | 00 · Habitação e estacionamento | FLOOR | Contentor · pintura 1
2 x Contentor · piso ou teto | 00 · Habitação e estacionamento | FLOOR | Contentor · pintura 2

# IfcStair, Jardim · escada pela fachada poente
In: 00 · Habitação e estacionamento
PredefinedType: STRAIGHT_RUN_STAIR
Pset_CasaProvenance - DesignSource: Casa Sobreposta / configuration.json; ReferenceFile: 260617_CasaDFL_Estrutura_Terreno.ifc; ConstructionBasis: DESIGN_ASSUMPTION; Note: West-facing descent; no south opening. Survey-based concept.

# IfcStairFlight, Jardim · lanço poente
In: 00 · Habitação e estacionamento
NumberOfRisers: 12; NumberOfTreads: 11; RiserHeight: 0.159167 m; TreadLength: 0.3 m; PredefinedType: STRAIGHT; Material: Betão armado / Stahlbeton
Pset_CasaProvenance - DesignSource: Casa Sobreposta / configuration.json; ReferenceFile: 260617_CasaDFL_Estrutura_Terreno.ifc; ConstructionBasis: DESIGN_ASSUMPTION

# IfcTank: RAINWATER_CISTERN, Cisterna · reservatório pluvial de estudo
In: -01 · Cisterna sob o terraço
PredefinedType: STORAGE
Pset_CasaProvenance - DesignSource: Casa Sobreposta / configuration.json; ReferenceFile: 260617_CasaDFL_Estrutura_Terreno.ifc; ConstructionBasis: DESIGN_ASSUMPTION; Note: Composite concrete vessel; provisional geometry only. No ordinary occupancy or stair access. Water depth and capacity to design.
Pset_CasaCistern - InternalPlanArea_m2: 17.8125; WaterDepthAssumed_m: 2; GeometricWaterVolume_m3: 35.625; SoffitClearanceAboveWater_m: 0.31; Status: Provisional water envelope; hydrostatic, uplift, watertightness, filtration, overflow and maintenance design pending

# IfcWall (89)
In: 00 · Habitação e estacionamento
Pset_CasaProvenance - DesignSource: Casa Sobreposta / configuration.json; ReferenceFile: 260617_CasaDFL_Estrutura_Terreno.ifc
Name | Material | ConstructionBasis | Pset_CasaProvenance, Note
Divisória 1 · OSB 22 mm nas duas faces | OSB, Lã mineral / Mineralwolle 2 | ADAPTED_REFERENCE | Original centreline/door positions preserved; schematic footprint widened 20 mm per side. 22 mm OSB linings; mineral wool core; stud layout not developed.
Divisória 2 · OSB 22 mm nas duas faces | OSB, Lã mineral / Mineralwolle 2 | ADAPTED_REFERENCE | Original centreline/door positions preserved; schematic footprint widened 20 mm per side. 22 mm OSB linings; mineral wool core; stud layout not developed.
Divisória 3 · OSB 22 mm nas duas faces | OSB, Lã mineral / Mineralwolle 2 | ADAPTED_REFERENCE | Original centreline/door positions preserved; schematic footprint widened 20 mm per side. 22 mm OSB linings; mineral wool core; stud layout not developed.
Divisória 4 · OSB 22 mm nas duas faces | OSB, Lã mineral / Mineralwolle 2 | ADAPTED_REFERENCE | Original centreline/door positions preserved; schematic footprint widened 20 mm per side. 22 mm OSB linings; mineral wool core; stud layout not developed.
Fachada norte · sandwich Casa DFL | Aço pintado / Stahl lackiert 0.005 m, Lã mineral / Mineralwolle 2 0.12 m, Aço pintado / Stahl lackiert 0.00516 m | ADAPTED_REFERENCE | Pset_CasaAssembly - OverallThickness_m: 0.13016; SourceModelSkinThicknesses_m: 0.005 / 0.00516; Core_m: 0.12; Note: Source geometry retained; commercial sheet specification not established.
Separação do estacionamento | Aço pintado / Stahl lackiert 0.005 m, Lã mineral / Mineralwolle 2 0.12 m, Aço pintado / Stahl lackiert 0.00516 m | ADAPTED_REFERENCE | Pset_CasaAssembly - OverallThickness_m: 0.13016; SourceModelSkinThicknesses_m: 0.005 / 0.00516; Core_m: 0.12; Note: Source geometry retained; commercial sheet specification not established.
Painel opaco sul 0 | Aço pintado / Stahl lackiert 0.005 m, Lã mineral / Mineralwolle 2 0.12 m, Aço pintado / Stahl lackiert 0.00516 m | ADAPTED_REFERENCE | Pset_CasaAssembly - OverallThickness_m: 0.13016; SourceModelSkinThicknesses_m: 0.005 / 0.00516; Core_m: 0.12; Note: Source geometry retained; commercial sheet specification not established.
Painel opaco sul 1 | Aço pintado / Stahl lackiert 0.005 m, Lã mineral / Mineralwolle 2 0.12 m, Aço pintado / Stahl lackiert 0.00516 m | ADAPTED_REFERENCE | Pset_CasaAssembly - OverallThickness_m: 0.13016; SourceModelSkinThicknesses_m: 0.005 / 0.00516; Core_m: 0.12; Note: Source geometry retained; commercial sheet specification not established.
Painel opaco sul 3 | Aço pintado / Stahl lackiert 0.005 m, Lã mineral / Mineralwolle 2 0.12 m, Aço pintado / Stahl lackiert 0.00516 m | ADAPTED_REFERENCE | Pset_CasaAssembly - OverallThickness_m: 0.13016; SourceModelSkinThicknesses_m: 0.005 / 0.00516; Core_m: 0.12; Note: Source geometry retained; commercial sheet specification not established.
Painel opaco sul 5 | Aço pintado / Stahl lackiert 0.005 m, Lã mineral / Mineralwolle 2 0.12 m, Aço pintado / Stahl lackiert 0.00516 m | ADAPTED_REFERENCE | Pset_CasaAssembly - OverallThickness_m: 0.13016; SourceModelSkinThicknesses_m: 0.005 / 0.00516; Core_m: 0.12; Note: Source geometry retained; commercial sheet specification not established.
Painel opaco sul 7 | Aço pintado / Stahl lackiert 0.005 m, Lã mineral / Mineralwolle 2 0.12 m, Aço pintado / Stahl lackiert 0.00516 m | ADAPTED_REFERENCE | Pset_CasaAssembly - OverallThickness_m: 0.13016; SourceModelSkinThicknesses_m: 0.005 / 0.00516; Core_m: 0.12; Note: Source geometry retained; commercial sheet specification not established.
Painel opaco sul 9 | Aço pintado / Stahl lackiert 0.005 m, Lã mineral / Mineralwolle 2 0.12 m, Aço pintado / Stahl lackiert 0.00516 m | ADAPTED_REFERENCE | Pset_CasaAssembly - OverallThickness_m: 0.13016; SourceModelSkinThicknesses_m: 0.005 / 0.00516; Core_m: 0.12; Note: Source geometry retained; commercial sheet specification not established.
Painel opaco sul 11 | Aço pintado / Stahl lackiert 0.005 m, Lã mineral / Mineralwolle 2 0.12 m, Aço pintado / Stahl lackiert 0.00516 m | ADAPTED_REFERENCE | Pset_CasaAssembly - OverallThickness_m: 0.13016; SourceModelSkinThicknesses_m: 0.005 / 0.00516; Core_m: 0.12; Note: Source geometry retained; commercial sheet specification not established.
2 x Fachada · remate sob frechal | Madeira / Bauholz | DESIGN_ASSUMPTION
74 x Divisória · prolongamento até ao forro | OSB | DESIGN_ASSUMPTION | R09 concept geometry; dimensions and connections not structurally verified.

# IfcWall: Cisterna · parede nascente
In: -01 · Cisterna sob o terraço
PredefinedType: USERDEFINED; Material: Betão armado / Stahlbeton
Pset_CasaProvenance - DesignSource: Casa Sobreposta / configuration.json; ReferenceFile: 260617_CasaDFL_Estrutura_Terreno.ifc; ConstructionBasis: DESIGN_ASSUMPTION; Note: 250 mm RC study wall, waterproofing and joints to detail; no retaining capacity asserted.

# IfcWall: Cisterna · parede norte
In: -01 · Cisterna sob o terraço
PredefinedType: USERDEFINED; Material: Betão armado / Stahlbeton
Pset_CasaProvenance - DesignSource: Casa Sobreposta / configuration.json; ReferenceFile: 260617_CasaDFL_Estrutura_Terreno.ifc; ConstructionBasis: DESIGN_ASSUMPTION; Note: 250 mm RC study wall, waterproofing and joints to detail; no retaining capacity asserted.

# IfcWall: Cisterna · parede poente
In: -01 · Cisterna sob o terraço
PredefinedType: USERDEFINED; Material: Betão armado / Stahlbeton
Pset_CasaProvenance - DesignSource: Casa Sobreposta / configuration.json; ReferenceFile: 260617_CasaDFL_Estrutura_Terreno.ifc; ConstructionBasis: DESIGN_ASSUMPTION; Note: 250 mm RC study wall, waterproofing and joints to detail; no retaining capacity asserted.

# IfcWall: Cisterna · parede sul
In: -01 · Cisterna sob o terraço
PredefinedType: USERDEFINED; Material: Betão armado / Stahlbeton
Pset_CasaProvenance - DesignSource: Casa Sobreposta / configuration.json; ReferenceFile: 260617_CasaDFL_Estrutura_Terreno.ifc; ConstructionBasis: DESIGN_ASSUMPTION; Note: 250 mm RC study wall, waterproofing and joints to detail; no retaining capacity asserted.

# IfcWindow (10)
In: 00 · Habitação e estacionamento
PredefinedType: WINDOW; PartitioningType: SINGLE_PANEL; Material: Vidro / Normalglas
Pset_CasaProvenance - DesignSource: Casa Sobreposta / configuration.json; ReferenceFile: 260617_CasaDFL_Estrutura_Terreno.ifc; ConstructionBasis: DESIGN_ASSUMPTION
Name | OverallHeight (m) | OverallWidth (m)
Rasgo norte 1 | 0.3 | 3.79
Rasgo norte 2 | 0.3 | 3.79
Rasgo norte 3 | 0.3 | 3.79
Rasgo norte 4 | 0.3 | 3.79
Rasgo norte 5 | 0.3 | 3.79
Rasgo norte 6 | 0.3 | 3.79
Rasgo norte 7 | 0.3 | 0.71
Fachada poente integralmente envidraçada · módulo 1 | 3 | 1.55 | Pset_CasaGlazedFacade - Revision: R02 · kiwi pergola; Facade: WEST / highlighted end in user sketch; Infill: Full-height glazing; no opaque infill; GlazingSpecification: 8 mm nominal representation only; insulated safety glazing assembly to specify
Fachada poente integralmente envidraçada · módulo 2 | 3 | 1.55 | Pset_CasaGlazedFacade - Revision: R02 · kiwi pergola; Facade: WEST / highlighted end in user sketch; Infill: Full-height glazing; no opaque infill; GlazingSpecification: 8 mm nominal representation only; insulated safety glazing assembly to specify
Fachada poente integralmente envidraçada · módulo 3 | 3 | 1.55 | Pset_CasaGlazedFacade - Revision: R02 · kiwi pergola; Facade: WEST / highlighted end in user sketch; Infill: Full-height glazing; no opaque infill; GlazingSpecification: 8 mm nominal representation only; insulated safety glazing assembly to specify
